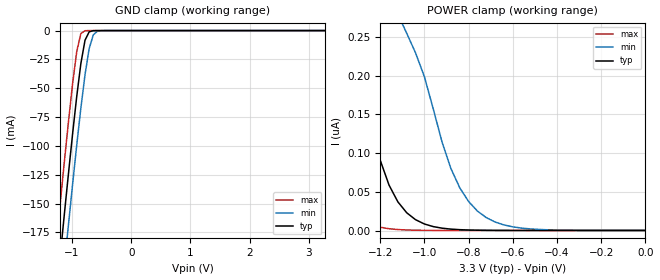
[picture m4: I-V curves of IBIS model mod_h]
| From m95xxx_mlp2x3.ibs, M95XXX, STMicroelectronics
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|   Model mod_h
[Model]   mod_h
Model_type Input
Vinl   =   1.00V
Vinh   =   2.30V
C_comp   2.119pF   2.024pF   2.323pF
[Temperature Range]  25.0000   85.0000   -40.0000
[Voltage Range]   3.3000V   1.7000V   5.5000V
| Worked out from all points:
|   GND clamp passes 1 mA (typ) near -0.70 V on its own axis
[GND_clamp]
|Voltage   I(typ)   I(min)   I(max)
-3.3V     -1.355A    -1.397A    -1.313A
-1.27V    -233mA     -277.9mA   -187.4mA
-1.2V     -196.1mA   -241mA     -150.5mA
-1.13V    -159.7mA   -204.5mA   -114.2mA
-1.06V    -124.1mA   -168.5mA   -79.16mA
-920mV    -57.12mA   -99.32mA   -18.15mA
-850mV    -28.51mA   -67.14mA   -2.609mA
-780mV    -8.357mA   -38.23mA   -131.1uA
-710mV    -1.089mA   -15.64mA   -5.451uA
-640mV    -95.71uA   -3.67mA    -224.5nA
-570mV    -7.943uA   -542uA     -9.245nA
3.28V     6.871pA    47.88pA    6.69pA
[POWER_clamp]
|Voltage   I(typ)   I(min)   I(max)
-3.28V    7.333uA    3.515uA    30.63uA
-1.52V    1.132uA    576.7nA    342.4nA
-1.48V    902.4nA    542.6nA    225.9nA
-1.4V     537.7nA    477.2nA    85.81nA
-1.32V    288.1nA    415.7nA    27.81nA
-1.2V     90.95nA    330.9nA    4.299nA
-1.12V    37nA       279.4nA    1.214nA
-1.04V    13.98nA    229.4nA    382.2pA
-880mV    1.802nA    80.04nA    105.6pA
-760mV    405.8pA    25.1nA     91.09pA
-560mV    74.59pA    3.087nA    87.52pA
0V        47.31pA    115.2pA    79.22pA
